VERSION 5.7 ;
BUSBITCHARS "[]" ;
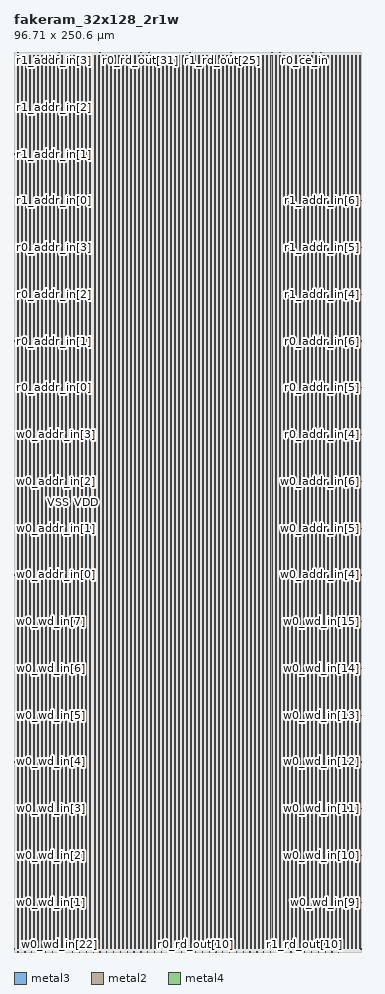
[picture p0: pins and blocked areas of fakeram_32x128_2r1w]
MACRO fakeram_32x128_2r1w
  FOREIGN fakeram_32x128_2r1w 0 0 ;
  SYMMETRY X Y R90 ;
  SIZE 96.710 BY 250.600 ;
  CLASS BLOCK ;
  PIN w0_wd_in[0]
    DIRECTION INPUT ;
    USE SIGNAL ;
    SHAPE ABUTMENT ;
    PORT
      LAYER metal3 ;
      RECT 0.000 0.805 0.210 0.875 ;
    END
  END w0_wd_in[0]
  PIN w0_wd_in[1]
    DIRECTION INPUT ;
    USE SIGNAL ;
    SHAPE ABUTMENT ;
    PORT
      LAYER metal3 ;
      RECT 0.000 13.825 0.210 13.895 ;
    END
  END w0_wd_in[1]
  PIN w0_wd_in[2]
    DIRECTION INPUT ;
    USE SIGNAL ;
    SHAPE ABUTMENT ;
    PORT
      LAYER metal3 ;
      RECT 0.000 26.845 0.210 26.915 ;
    END
  END w0_wd_in[2]
  PIN w0_wd_in[3]
    DIRECTION INPUT ;
    USE SIGNAL ;
    SHAPE ABUTMENT ;
    PORT
      LAYER metal3 ;
      RECT 0.000 39.865 0.210 39.935 ;
    END
  END w0_wd_in[3]
  PIN w0_wd_in[4]
    DIRECTION INPUT ;
    USE SIGNAL ;
    SHAPE ABUTMENT ;
    PORT
      LAYER metal3 ;
      RECT 0.000 52.885 0.210 52.955 ;
    END
  END w0_wd_in[4]
  PIN w0_wd_in[5]
    DIRECTION INPUT ;
    USE SIGNAL ;
    SHAPE ABUTMENT ;
    PORT
      LAYER metal3 ;
      RECT 0.000 65.905 0.210 65.975 ;
    END
  END w0_wd_in[5]
  PIN w0_wd_in[6]
    DIRECTION INPUT ;
    USE SIGNAL ;
    SHAPE ABUTMENT ;
    PORT
      LAYER metal3 ;
      RECT 0.000 78.925 0.210 78.995 ;
    END
  END w0_wd_in[6]
  PIN w0_wd_in[7]
    DIRECTION INPUT ;
    USE SIGNAL ;
    SHAPE ABUTMENT ;
    PORT
      LAYER metal3 ;
      RECT 0.000 91.945 0.210 92.015 ;
    END
  END w0_wd_in[7]
  PIN w0_wd_in[8]
    DIRECTION INPUT ;
    USE SIGNAL ;
    SHAPE ABUTMENT ;
    PORT
      LAYER metal3 ;
      RECT 96.500 0.805 96.710 0.875 ;
    END
  END w0_wd_in[8]
  PIN w0_wd_in[9]
    DIRECTION INPUT ;
    USE SIGNAL ;
    SHAPE ABUTMENT ;
    PORT
      LAYER metal3 ;
      RECT 96.500 13.825 96.710 13.895 ;
    END
  END w0_wd_in[9]
  PIN w0_wd_in[10]
    DIRECTION INPUT ;
    USE SIGNAL ;
    SHAPE ABUTMENT ;
    PORT
      LAYER metal3 ;
      RECT 96.500 26.845 96.710 26.915 ;
    END
  END w0_wd_in[10]
  PIN w0_wd_in[11]
    DIRECTION INPUT ;
    USE SIGNAL ;
    SHAPE ABUTMENT ;
    PORT
      LAYER metal3 ;
      RECT 96.500 39.865 96.710 39.935 ;
    END
  END w0_wd_in[11]
  PIN w0_wd_in[12]
    DIRECTION INPUT ;
    USE SIGNAL ;
    SHAPE ABUTMENT ;
    PORT
      LAYER metal3 ;
      RECT 96.500 52.885 96.710 52.955 ;
    END
  END w0_wd_in[12]
  PIN w0_wd_in[13]
    DIRECTION INPUT ;
    USE SIGNAL ;
    SHAPE ABUTMENT ;
    PORT
      LAYER metal3 ;
      RECT 96.500 65.905 96.710 65.975 ;
    END
  END w0_wd_in[13]
  PIN w0_wd_in[14]
    DIRECTION INPUT ;
    USE SIGNAL ;
    SHAPE ABUTMENT ;
    PORT
      LAYER metal3 ;
      RECT 96.500 78.925 96.710 78.995 ;
    END
  END w0_wd_in[14]
  PIN w0_wd_in[15]
    DIRECTION INPUT ;
    USE SIGNAL ;
    SHAPE ABUTMENT ;
    PORT
      LAYER metal3 ;
      RECT 96.500 91.945 96.710 92.015 ;
    END
  END w0_wd_in[15]
  PIN w0_wd_in[16]
    DIRECTION INPUT ;
    USE SIGNAL ;
    SHAPE ABUTMENT ;
    PORT
      LAYER metal2 ;
      RECT 1.105 0.000 1.175 0.210 ;
    END
  END w0_wd_in[16]
  PIN w0_wd_in[17]
    DIRECTION INPUT ;
    USE SIGNAL ;
    SHAPE ABUTMENT ;
    PORT
      LAYER metal2 ;
      RECT 3.005 0.000 3.075 0.210 ;
    END
  END w0_wd_in[17]
  PIN w0_wd_in[18]
    DIRECTION INPUT ;
    USE SIGNAL ;
    SHAPE ABUTMENT ;
    PORT
      LAYER metal2 ;
      RECT 4.905 0.000 4.975 0.210 ;
    END
  END w0_wd_in[18]
  PIN w0_wd_in[19]
    DIRECTION INPUT ;
    USE SIGNAL ;
    SHAPE ABUTMENT ;
    PORT
      LAYER metal2 ;
      RECT 6.805 0.000 6.875 0.210 ;
    END
  END w0_wd_in[19]
  PIN w0_wd_in[20]
    DIRECTION INPUT ;
    USE SIGNAL ;
    SHAPE ABUTMENT ;
    PORT
      LAYER metal2 ;
      RECT 8.705 0.000 8.775 0.210 ;
    END
  END w0_wd_in[20]
  PIN w0_wd_in[21]
    DIRECTION INPUT ;
    USE SIGNAL ;
    SHAPE ABUTMENT ;
    PORT
      LAYER metal2 ;
      RECT 10.605 0.000 10.675 0.210 ;
    END
  END w0_wd_in[21]
  PIN w0_wd_in[22]
    DIRECTION INPUT ;
    USE SIGNAL ;
    SHAPE ABUTMENT ;
    PORT
      LAYER metal2 ;
      RECT 12.505 0.000 12.575 0.210 ;
    END
  END w0_wd_in[22]
  PIN w0_wd_in[23]
    DIRECTION INPUT ;
    USE SIGNAL ;
    SHAPE ABUTMENT ;
    PORT
      LAYER metal2 ;
      RECT 14.405 0.000 14.475 0.210 ;
    END
  END w0_wd_in[23]
  PIN w0_wd_in[24]
    DIRECTION INPUT ;
    USE SIGNAL ;
    SHAPE ABUTMENT ;
    PORT
      LAYER metal2 ;
      RECT 16.305 0.000 16.375 0.210 ;
    END
  END w0_wd_in[24]
  PIN w0_wd_in[25]
    DIRECTION INPUT ;
    USE SIGNAL ;
    SHAPE ABUTMENT ;
    PORT
      LAYER metal2 ;
      RECT 18.205 0.000 18.275 0.210 ;
    END
  END w0_wd_in[25]
  PIN w0_wd_in[26]
    DIRECTION INPUT ;
    USE SIGNAL ;
    SHAPE ABUTMENT ;
    PORT
      LAYER metal2 ;
      RECT 20.105 0.000 20.175 0.210 ;
    END
  END w0_wd_in[26]
  PIN w0_wd_in[27]
    DIRECTION INPUT ;
    USE SIGNAL ;
    SHAPE ABUTMENT ;
    PORT
      LAYER metal2 ;
      RECT 22.005 0.000 22.075 0.210 ;
    END
  END w0_wd_in[27]
  PIN w0_wd_in[28]
    DIRECTION INPUT ;
    USE SIGNAL ;
    SHAPE ABUTMENT ;
    PORT
      LAYER metal2 ;
      RECT 23.905 0.000 23.975 0.210 ;
    END
  END w0_wd_in[28]
  PIN w0_wd_in[29]
    DIRECTION INPUT ;
    USE SIGNAL ;
    SHAPE ABUTMENT ;
    PORT
      LAYER metal2 ;
      RECT 25.805 0.000 25.875 0.210 ;
    END
  END w0_wd_in[29]
  PIN w0_wd_in[30]
    DIRECTION INPUT ;
    USE SIGNAL ;
    SHAPE ABUTMENT ;
    PORT
      LAYER metal2 ;
      RECT 27.705 0.000 27.775 0.210 ;
    END
  END w0_wd_in[30]
  PIN w0_wd_in[31]
    DIRECTION INPUT ;
    USE SIGNAL ;
    SHAPE ABUTMENT ;
    PORT
      LAYER metal2 ;
      RECT 29.605 0.000 29.675 0.210 ;
    END
  END w0_wd_in[31]
  PIN r0_rd_out[0]
    DIRECTION OUTPUT ;
    USE SIGNAL ;
    SHAPE ABUTMENT ;
    PORT
      LAYER metal2 ;
      RECT 31.505 0.000 31.575 0.210 ;
    END
  END r0_rd_out[0]
  PIN r0_rd_out[1]
    DIRECTION OUTPUT ;
    USE SIGNAL ;
    SHAPE ABUTMENT ;
    PORT
      LAYER metal2 ;
      RECT 33.405 0.000 33.475 0.210 ;
    END
  END r0_rd_out[1]
  PIN r0_rd_out[2]
    DIRECTION OUTPUT ;
    USE SIGNAL ;
    SHAPE ABUTMENT ;
    PORT
      LAYER metal2 ;
      RECT 35.305 0.000 35.375 0.210 ;
    END
  END r0_rd_out[2]
  PIN r0_rd_out[3]
    DIRECTION OUTPUT ;
    USE SIGNAL ;
    SHAPE ABUTMENT ;
    PORT
      LAYER metal2 ;
      RECT 37.205 0.000 37.275 0.210 ;
    END
  END r0_rd_out[3]
  PIN r0_rd_out[4]
    DIRECTION OUTPUT ;
    USE SIGNAL ;
    SHAPE ABUTMENT ;
    PORT
      LAYER metal2 ;
      RECT 39.105 0.000 39.175 0.210 ;
    END
  END r0_rd_out[4]
  PIN r0_rd_out[5]
    DIRECTION OUTPUT ;
    USE SIGNAL ;
    SHAPE ABUTMENT ;
    PORT
      LAYER metal2 ;
      RECT 41.005 0.000 41.075 0.210 ;
    END
  END r0_rd_out[5]
  PIN r0_rd_out[6]
    DIRECTION OUTPUT ;
    USE SIGNAL ;
    SHAPE ABUTMENT ;
    PORT
      LAYER metal2 ;
      RECT 42.905 0.000 42.975 0.210 ;
    END
  END r0_rd_out[6]
  PIN r0_rd_out[7]
    DIRECTION OUTPUT ;
    USE SIGNAL ;
    SHAPE ABUTMENT ;
    PORT
      LAYER metal2 ;
      RECT 44.805 0.000 44.875 0.210 ;
    END
  END r0_rd_out[7]
  PIN r0_rd_out[8]
    DIRECTION OUTPUT ;
    USE SIGNAL ;
    SHAPE ABUTMENT ;
    PORT
      LAYER metal2 ;
      RECT 46.705 0.000 46.775 0.210 ;
    END
  END r0_rd_out[8]
  PIN r0_rd_out[9]
    DIRECTION OUTPUT ;
    USE SIGNAL ;
    SHAPE ABUTMENT ;
    PORT
      LAYER metal2 ;
      RECT 48.605 0.000 48.675 0.210 ;
    END
  END r0_rd_out[9]
  PIN r0_rd_out[10]
    DIRECTION OUTPUT ;
    USE SIGNAL ;
    SHAPE ABUTMENT ;
    PORT
      LAYER metal2 ;
      RECT 50.505 0.000 50.575 0.210 ;
    END
  END r0_rd_out[10]
  PIN r0_rd_out[11]
    DIRECTION OUTPUT ;
    USE SIGNAL ;
    SHAPE ABUTMENT ;
    PORT
      LAYER metal2 ;
      RECT 52.405 0.000 52.475 0.210 ;
    END
  END r0_rd_out[11]
  PIN r0_rd_out[12]
    DIRECTION OUTPUT ;
    USE SIGNAL ;
    SHAPE ABUTMENT ;
    PORT
      LAYER metal2 ;
      RECT 54.305 0.000 54.375 0.210 ;
    END
  END r0_rd_out[12]
  PIN r0_rd_out[13]
    DIRECTION OUTPUT ;
    USE SIGNAL ;
    SHAPE ABUTMENT ;
    PORT
      LAYER metal2 ;
      RECT 56.205 0.000 56.275 0.210 ;
    END
  END r0_rd_out[13]
  PIN r0_rd_out[14]
    DIRECTION OUTPUT ;
    USE SIGNAL ;
    SHAPE ABUTMENT ;
    PORT
      LAYER metal2 ;
      RECT 58.105 0.000 58.175 0.210 ;
    END
  END r0_rd_out[14]
  PIN r0_rd_out[15]
    DIRECTION OUTPUT ;
    USE SIGNAL ;
    SHAPE ABUTMENT ;
    PORT
      LAYER metal2 ;
      RECT 60.005 0.000 60.075 0.210 ;
    END
  END r0_rd_out[15]
  PIN r0_rd_out[16]
    DIRECTION OUTPUT ;
    USE SIGNAL ;
    SHAPE ABUTMENT ;
    PORT
      LAYER metal2 ;
      RECT 1.105 250.390 1.175 250.600 ;
    END
  END r0_rd_out[16]
  PIN r0_rd_out[17]
    DIRECTION OUTPUT ;
    USE SIGNAL ;
    SHAPE ABUTMENT ;
    PORT
      LAYER metal2 ;
      RECT 3.385 250.390 3.455 250.600 ;
    END
  END r0_rd_out[17]
  PIN r0_rd_out[18]
    DIRECTION OUTPUT ;
    USE SIGNAL ;
    SHAPE ABUTMENT ;
    PORT
      LAYER metal2 ;
      RECT 5.665 250.390 5.735 250.600 ;
    END
  END r0_rd_out[18]
  PIN r0_rd_out[19]
    DIRECTION OUTPUT ;
    USE SIGNAL ;
    SHAPE ABUTMENT ;
    PORT
      LAYER metal2 ;
      RECT 7.945 250.390 8.015 250.600 ;
    END
  END r0_rd_out[19]
  PIN r0_rd_out[20]
    DIRECTION OUTPUT ;
    USE SIGNAL ;
    SHAPE ABUTMENT ;
    PORT
      LAYER metal2 ;
      RECT 10.225 250.390 10.295 250.600 ;
    END
  END r0_rd_out[20]
  PIN r0_rd_out[21]
    DIRECTION OUTPUT ;
    USE SIGNAL ;
    SHAPE ABUTMENT ;
    PORT
      LAYER metal2 ;
      RECT 12.505 250.390 12.575 250.600 ;
    END
  END r0_rd_out[21]
  PIN r0_rd_out[22]
    DIRECTION OUTPUT ;
    USE SIGNAL ;
    SHAPE ABUTMENT ;
    PORT
      LAYER metal2 ;
      RECT 14.785 250.390 14.855 250.600 ;
    END
  END r0_rd_out[22]
  PIN r0_rd_out[23]
    DIRECTION OUTPUT ;
    USE SIGNAL ;
    SHAPE ABUTMENT ;
    PORT
      LAYER metal2 ;
      RECT 17.065 250.390 17.135 250.600 ;
    END
  END r0_rd_out[23]
  PIN r0_rd_out[24]
    DIRECTION OUTPUT ;
    USE SIGNAL ;
    SHAPE ABUTMENT ;
    PORT
      LAYER metal2 ;
      RECT 19.345 250.390 19.415 250.600 ;
    END
  END r0_rd_out[24]
  PIN r0_rd_out[25]
    DIRECTION OUTPUT ;
    USE SIGNAL ;
    SHAPE ABUTMENT ;
    PORT
      LAYER metal2 ;
      RECT 21.625 250.390 21.695 250.600 ;
    END
  END r0_rd_out[25]
  PIN r0_rd_out[26]
    DIRECTION OUTPUT ;
    USE SIGNAL ;
    SHAPE ABUTMENT ;
    PORT
      LAYER metal2 ;
      RECT 23.905 250.390 23.975 250.600 ;
    END
  END r0_rd_out[26]
  PIN r0_rd_out[27]
    DIRECTION OUTPUT ;
    USE SIGNAL ;
    SHAPE ABUTMENT ;
    PORT
      LAYER metal2 ;
      RECT 26.185 250.390 26.255 250.600 ;
    END
  END r0_rd_out[27]
  PIN r0_rd_out[28]
    DIRECTION OUTPUT ;
    USE SIGNAL ;
    SHAPE ABUTMENT ;
    PORT
      LAYER metal2 ;
      RECT 28.465 250.390 28.535 250.600 ;
    END
  END r0_rd_out[28]
  PIN r0_rd_out[29]
    DIRECTION OUTPUT ;
    USE SIGNAL ;
    SHAPE ABUTMENT ;
    PORT
      LAYER metal2 ;
      RECT 30.745 250.390 30.815 250.600 ;
    END
  END r0_rd_out[29]
  PIN r0_rd_out[30]
    DIRECTION OUTPUT ;
    USE SIGNAL ;
    SHAPE ABUTMENT ;
    PORT
      LAYER metal2 ;
      RECT 33.025 250.390 33.095 250.600 ;
    END
  END r0_rd_out[30]
  PIN r0_rd_out[31]
    DIRECTION OUTPUT ;
    USE SIGNAL ;
    SHAPE ABUTMENT ;
    PORT
      LAYER metal2 ;
      RECT 35.305 250.390 35.375 250.600 ;
    END
  END r0_rd_out[31]
  PIN r1_rd_out[0]
    DIRECTION OUTPUT ;
    USE SIGNAL ;
    SHAPE ABUTMENT ;
    PORT
      LAYER metal2 ;
      RECT 61.905 0.000 61.975 0.210 ;
    END
  END r1_rd_out[0]
  PIN r1_rd_out[1]
    DIRECTION OUTPUT ;
    USE SIGNAL ;
    SHAPE ABUTMENT ;
    PORT
      LAYER metal2 ;
      RECT 63.805 0.000 63.875 0.210 ;
    END
  END r1_rd_out[1]
  PIN r1_rd_out[2]
    DIRECTION OUTPUT ;
    USE SIGNAL ;
    SHAPE ABUTMENT ;
    PORT
      LAYER metal2 ;
      RECT 65.705 0.000 65.775 0.210 ;
    END
  END r1_rd_out[2]
  PIN r1_rd_out[3]
    DIRECTION OUTPUT ;
    USE SIGNAL ;
    SHAPE ABUTMENT ;
    PORT
      LAYER metal2 ;
      RECT 67.605 0.000 67.675 0.210 ;
    END
  END r1_rd_out[3]
  PIN r1_rd_out[4]
    DIRECTION OUTPUT ;
    USE SIGNAL ;
    SHAPE ABUTMENT ;
    PORT
      LAYER metal2 ;
      RECT 69.505 0.000 69.575 0.210 ;
    END
  END r1_rd_out[4]
  PIN r1_rd_out[5]
    DIRECTION OUTPUT ;
    USE SIGNAL ;
    SHAPE ABUTMENT ;
    PORT
      LAYER metal2 ;
      RECT 71.405 0.000 71.475 0.210 ;
    END
  END r1_rd_out[5]
  PIN r1_rd_out[6]
    DIRECTION OUTPUT ;
    USE SIGNAL ;
    SHAPE ABUTMENT ;
    PORT
      LAYER metal2 ;
      RECT 73.305 0.000 73.375 0.210 ;
    END
  END r1_rd_out[6]
  PIN r1_rd_out[7]
    DIRECTION OUTPUT ;
    USE SIGNAL ;
    SHAPE ABUTMENT ;
    PORT
      LAYER metal2 ;
      RECT 75.205 0.000 75.275 0.210 ;
    END
  END r1_rd_out[7]
  PIN r1_rd_out[8]
    DIRECTION OUTPUT ;
    USE SIGNAL ;
    SHAPE ABUTMENT ;
    PORT
      LAYER metal2 ;
      RECT 77.105 0.000 77.175 0.210 ;
    END
  END r1_rd_out[8]
  PIN r1_rd_out[9]
    DIRECTION OUTPUT ;
    USE SIGNAL ;
    SHAPE ABUTMENT ;
    PORT
      LAYER metal2 ;
      RECT 79.005 0.000 79.075 0.210 ;
    END
  END r1_rd_out[9]
  PIN r1_rd_out[10]
    DIRECTION OUTPUT ;
    USE SIGNAL ;
    SHAPE ABUTMENT ;
    PORT
      LAYER metal2 ;
      RECT 80.905 0.000 80.975 0.210 ;
    END
  END r1_rd_out[10]
  PIN r1_rd_out[11]
    DIRECTION OUTPUT ;
    USE SIGNAL ;
    SHAPE ABUTMENT ;
    PORT
      LAYER metal2 ;
      RECT 82.805 0.000 82.875 0.210 ;
    END
  END r1_rd_out[11]
  PIN r1_rd_out[12]
    DIRECTION OUTPUT ;
    USE SIGNAL ;
    SHAPE ABUTMENT ;
    PORT
      LAYER metal2 ;
      RECT 84.705 0.000 84.775 0.210 ;
    END
  END r1_rd_out[12]
  PIN r1_rd_out[13]
    DIRECTION OUTPUT ;
    USE SIGNAL ;
    SHAPE ABUTMENT ;
    PORT
      LAYER metal2 ;
      RECT 86.605 0.000 86.675 0.210 ;
    END
  END r1_rd_out[13]
  PIN r1_rd_out[14]
    DIRECTION OUTPUT ;
    USE SIGNAL ;
    SHAPE ABUTMENT ;
    PORT
      LAYER metal2 ;
      RECT 88.505 0.000 88.575 0.210 ;
    END
  END r1_rd_out[14]
  PIN r1_rd_out[15]
    DIRECTION OUTPUT ;
    USE SIGNAL ;
    SHAPE ABUTMENT ;
    PORT
      LAYER metal2 ;
      RECT 90.405 0.000 90.475 0.210 ;
    END
  END r1_rd_out[15]
  PIN r1_rd_out[16]
    DIRECTION OUTPUT ;
    USE SIGNAL ;
    SHAPE ABUTMENT ;
    PORT
      LAYER metal2 ;
      RECT 37.585 250.390 37.655 250.600 ;
    END
  END r1_rd_out[16]
  PIN r1_rd_out[17]
    DIRECTION OUTPUT ;
    USE SIGNAL ;
    SHAPE ABUTMENT ;
    PORT
      LAYER metal2 ;
      RECT 39.865 250.390 39.935 250.600 ;
    END
  END r1_rd_out[17]
  PIN r1_rd_out[18]
    DIRECTION OUTPUT ;
    USE SIGNAL ;
    SHAPE ABUTMENT ;
    PORT
      LAYER metal2 ;
      RECT 42.145 250.390 42.215 250.600 ;
    END
  END r1_rd_out[18]
  PIN r1_rd_out[19]
    DIRECTION OUTPUT ;
    USE SIGNAL ;
    SHAPE ABUTMENT ;
    PORT
      LAYER metal2 ;
      RECT 44.425 250.390 44.495 250.600 ;
    END
  END r1_rd_out[19]
  PIN r1_rd_out[20]
    DIRECTION OUTPUT ;
    USE SIGNAL ;
    SHAPE ABUTMENT ;
    PORT
      LAYER metal2 ;
      RECT 46.705 250.390 46.775 250.600 ;
    END
  END r1_rd_out[20]
  PIN r1_rd_out[21]
    DIRECTION OUTPUT ;
    USE SIGNAL ;
    SHAPE ABUTMENT ;
    PORT
      LAYER metal2 ;
      RECT 48.985 250.390 49.055 250.600 ;
    END
  END r1_rd_out[21]
  PIN r1_rd_out[22]
    DIRECTION OUTPUT ;
    USE SIGNAL ;
    SHAPE ABUTMENT ;
    PORT
      LAYER metal2 ;
      RECT 51.265 250.390 51.335 250.600 ;
    END
  END r1_rd_out[22]
  PIN r1_rd_out[23]
    DIRECTION OUTPUT ;
    USE SIGNAL ;
    SHAPE ABUTMENT ;
    PORT
      LAYER metal2 ;
      RECT 53.545 250.390 53.615 250.600 ;
    END
  END r1_rd_out[23]
  PIN r1_rd_out[24]
    DIRECTION OUTPUT ;
    USE SIGNAL ;
    SHAPE ABUTMENT ;
    PORT
      LAYER metal2 ;
      RECT 55.825 250.390 55.895 250.600 ;
    END
  END r1_rd_out[24]
  PIN r1_rd_out[25]
    DIRECTION OUTPUT ;
    USE SIGNAL ;
    SHAPE ABUTMENT ;
    PORT
      LAYER metal2 ;
      RECT 58.105 250.390 58.175 250.600 ;
    END
  END r1_rd_out[25]
  PIN r1_rd_out[26]
    DIRECTION OUTPUT ;
    USE SIGNAL ;
    SHAPE ABUTMENT ;
    PORT
      LAYER metal2 ;
      RECT 60.385 250.390 60.455 250.600 ;
    END
  END r1_rd_out[26]
  PIN r1_rd_out[27]
    DIRECTION OUTPUT ;
    USE SIGNAL ;
    SHAPE ABUTMENT ;
    PORT
      LAYER metal2 ;
      RECT 62.665 250.390 62.735 250.600 ;
    END
  END r1_rd_out[27]
  PIN r1_rd_out[28]
    DIRECTION OUTPUT ;
    USE SIGNAL ;
    SHAPE ABUTMENT ;
    PORT
      LAYER metal2 ;
      RECT 64.945 250.390 65.015 250.600 ;
    END
  END r1_rd_out[28]
  PIN r1_rd_out[29]
    DIRECTION OUTPUT ;
    USE SIGNAL ;
    SHAPE ABUTMENT ;
    PORT
      LAYER metal2 ;
      RECT 67.225 250.390 67.295 250.600 ;
    END
  END r1_rd_out[29]
  PIN r1_rd_out[30]
    DIRECTION OUTPUT ;
    USE SIGNAL ;
    SHAPE ABUTMENT ;
    PORT
      LAYER metal2 ;
      RECT 69.505 250.390 69.575 250.600 ;
    END
  END r1_rd_out[30]
  PIN r1_rd_out[31]
    DIRECTION OUTPUT ;
    USE SIGNAL ;
    SHAPE ABUTMENT ;
    PORT
      LAYER metal2 ;
      RECT 71.785 250.390 71.855 250.600 ;
    END
  END r1_rd_out[31]
  PIN w0_addr_in[0]
    DIRECTION INPUT ;
    USE SIGNAL ;
    SHAPE ABUTMENT ;
    PORT
      LAYER metal3 ;
      RECT 0.000 104.965 0.210 105.035 ;
    END
  END w0_addr_in[0]
  PIN w0_addr_in[1]
    DIRECTION INPUT ;
    USE SIGNAL ;
    SHAPE ABUTMENT ;
    PORT
      LAYER metal3 ;
      RECT 0.000 117.985 0.210 118.055 ;
    END
  END w0_addr_in[1]
  PIN w0_addr_in[2]
    DIRECTION INPUT ;
    USE SIGNAL ;
    SHAPE ABUTMENT ;
    PORT
      LAYER metal3 ;
      RECT 0.000 131.005 0.210 131.075 ;
    END
  END w0_addr_in[2]
  PIN w0_addr_in[3]
    DIRECTION INPUT ;
    USE SIGNAL ;
    SHAPE ABUTMENT ;
    PORT
      LAYER metal3 ;
      RECT 0.000 144.025 0.210 144.095 ;
    END
  END w0_addr_in[3]
  PIN w0_addr_in[4]
    DIRECTION INPUT ;
    USE SIGNAL ;
    SHAPE ABUTMENT ;
    PORT
      LAYER metal3 ;
      RECT 96.500 104.965 96.710 105.035 ;
    END
  END w0_addr_in[4]
  PIN w0_addr_in[5]
    DIRECTION INPUT ;
    USE SIGNAL ;
    SHAPE ABUTMENT ;
    PORT
      LAYER metal3 ;
      RECT 96.500 117.985 96.710 118.055 ;
    END
  END w0_addr_in[5]
  PIN w0_addr_in[6]
    DIRECTION INPUT ;
    USE SIGNAL ;
    SHAPE ABUTMENT ;
    PORT
      LAYER metal3 ;
      RECT 96.500 131.005 96.710 131.075 ;
    END
  END w0_addr_in[6]
  PIN r0_addr_in[0]
    DIRECTION INPUT ;
    USE SIGNAL ;
    SHAPE ABUTMENT ;
    PORT
      LAYER metal3 ;
      RECT 0.000 157.045 0.210 157.115 ;
    END
  END r0_addr_in[0]
  PIN r0_addr_in[1]
    DIRECTION INPUT ;
    USE SIGNAL ;
    SHAPE ABUTMENT ;
    PORT
      LAYER metal3 ;
      RECT 0.000 170.065 0.210 170.135 ;
    END
  END r0_addr_in[1]
  PIN r0_addr_in[2]
    DIRECTION INPUT ;
    USE SIGNAL ;
    SHAPE ABUTMENT ;
    PORT
      LAYER metal3 ;
      RECT 0.000 183.085 0.210 183.155 ;
    END
  END r0_addr_in[2]
  PIN r0_addr_in[3]
    DIRECTION INPUT ;
    USE SIGNAL ;
    SHAPE ABUTMENT ;
    PORT
      LAYER metal3 ;
      RECT 0.000 196.105 0.210 196.175 ;
    END
  END r0_addr_in[3]
  PIN r0_addr_in[4]
    DIRECTION INPUT ;
    USE SIGNAL ;
    SHAPE ABUTMENT ;
    PORT
      LAYER metal3 ;
      RECT 96.500 144.025 96.710 144.095 ;
    END
  END r0_addr_in[4]
  PIN r0_addr_in[5]
    DIRECTION INPUT ;
    USE SIGNAL ;
    SHAPE ABUTMENT ;
    PORT
      LAYER metal3 ;
      RECT 96.500 157.045 96.710 157.115 ;
    END
  END r0_addr_in[5]
  PIN r0_addr_in[6]
    DIRECTION INPUT ;
    USE SIGNAL ;
    SHAPE ABUTMENT ;
    PORT
      LAYER metal3 ;
      RECT 96.500 170.065 96.710 170.135 ;
    END
  END r0_addr_in[6]
  PIN r1_addr_in[0]
    DIRECTION INPUT ;
    USE SIGNAL ;
    SHAPE ABUTMENT ;
    PORT
      LAYER metal3 ;
      RECT 0.000 209.125 0.210 209.195 ;
    END
  END r1_addr_in[0]
  PIN r1_addr_in[1]
    DIRECTION INPUT ;
    USE SIGNAL ;
    SHAPE ABUTMENT ;
    PORT
      LAYER metal3 ;
      RECT 0.000 222.145 0.210 222.215 ;
    END
  END r1_addr_in[1]
  PIN r1_addr_in[2]
    DIRECTION INPUT ;
    USE SIGNAL ;
    SHAPE ABUTMENT ;
    PORT
      LAYER metal3 ;
      RECT 0.000 235.165 0.210 235.235 ;
    END
  END r1_addr_in[2]
  PIN r1_addr_in[3]
    DIRECTION INPUT ;
    USE SIGNAL ;
    SHAPE ABUTMENT ;
    PORT
      LAYER metal3 ;
      RECT 0.000 248.185 0.210 248.255 ;
    END
  END r1_addr_in[3]
  PIN r1_addr_in[4]
    DIRECTION INPUT ;
    USE SIGNAL ;
    SHAPE ABUTMENT ;
    PORT
      LAYER metal3 ;
      RECT 96.500 183.085 96.710 183.155 ;
    END
  END r1_addr_in[4]
  PIN r1_addr_in[5]
    DIRECTION INPUT ;
    USE SIGNAL ;
    SHAPE ABUTMENT ;
    PORT
      LAYER metal3 ;
      RECT 96.500 196.105 96.710 196.175 ;
    END
  END r1_addr_in[5]
  PIN r1_addr_in[6]
    DIRECTION INPUT ;
    USE SIGNAL ;
    SHAPE ABUTMENT ;
    PORT
      LAYER metal3 ;
      RECT 96.500 209.125 96.710 209.195 ;
    END
  END r1_addr_in[6]
  PIN w0_we_in
    DIRECTION INPUT ;
    USE SIGNAL ;
    SHAPE ABUTMENT ;
    PORT
      LAYER metal2 ;
      RECT 74.065 250.390 74.135 250.600 ;
    END
  END w0_we_in
  PIN w0_ce_in
    DIRECTION INPUT ;
    USE SIGNAL ;
    SHAPE ABUTMENT ;
    PORT
      LAYER metal2 ;
      RECT 76.345 250.390 76.415 250.600 ;
    END
  END w0_ce_in
  PIN w0_clk
    DIRECTION INPUT ;
    USE SIGNAL ;
    SHAPE ABUTMENT ;
    PORT
      LAYER metal2 ;
      RECT 78.625 250.390 78.695 250.600 ;
    END
  END w0_clk
  PIN r0_ce_in
    DIRECTION INPUT ;
    USE SIGNAL ;
    SHAPE ABUTMENT ;
    PORT
      LAYER metal2 ;
      RECT 80.905 250.390 80.975 250.600 ;
    END
  END r0_ce_in
  PIN r0_clk
    DIRECTION INPUT ;
    USE SIGNAL ;
    SHAPE ABUTMENT ;
    PORT
      LAYER metal2 ;
      RECT 83.185 250.390 83.255 250.600 ;
    END
  END r0_clk
  PIN r1_ce_in
    DIRECTION INPUT ;
    USE SIGNAL ;
    SHAPE ABUTMENT ;
    PORT
      LAYER metal2 ;
      RECT 85.465 250.390 85.535 250.600 ;
    END
  END r1_ce_in
  PIN r1_clk
    DIRECTION INPUT ;
    USE SIGNAL ;
    SHAPE ABUTMENT ;
    PORT
      LAYER metal2 ;
      RECT 87.745 250.390 87.815 250.600 ;
    END
  END r1_clk
  PIN VSS
    DIRECTION INOUT ;
    USE GROUND ;
    PORT
      LAYER metal4 ;
      RECT 1.000 0.840 1.280 249.760 ;
      RECT 3.240 0.840 3.520 249.760 ;
      RECT 5.480 0.840 5.760 249.760 ;
      RECT 7.720 0.840 8.000 249.760 ;
      RECT 9.960 0.840 10.240 249.760 ;
      RECT 12.200 0.840 12.480 249.760 ;
      RECT 14.440 0.840 14.720 249.760 ;
      RECT 16.680 0.840 16.960 249.760 ;
      RECT 18.920 0.840 19.200 249.760 ;
      RECT 21.160 0.840 21.440 249.760 ;
      RECT 23.400 0.840 23.680 249.760 ;
      RECT 25.640 0.840 25.920 249.760 ;
      RECT 27.880 0.840 28.160 249.760 ;
      RECT 30.120 0.840 30.400 249.760 ;
      RECT 32.360 0.840 32.640 249.760 ;
      RECT 34.600 0.840 34.880 249.760 ;
      RECT 36.840 0.840 37.120 249.760 ;
      RECT 39.080 0.840 39.360 249.760 ;
      RECT 41.320 0.840 41.600 249.760 ;
      RECT 43.560 0.840 43.840 249.760 ;
      RECT 45.800 0.840 46.080 249.760 ;
      RECT 48.040 0.840 48.320 249.760 ;
      RECT 50.280 0.840 50.560 249.760 ;
      RECT 52.520 0.840 52.800 249.760 ;
      RECT 54.760 0.840 55.040 249.760 ;
      RECT 57.000 0.840 57.280 249.760 ;
      RECT 59.240 0.840 59.520 249.760 ;
      RECT 61.480 0.840 61.760 249.760 ;
      RECT 63.720 0.840 64.000 249.760 ;
      RECT 65.960 0.840 66.240 249.760 ;
      RECT 68.200 0.840 68.480 249.760 ;
      RECT 70.440 0.840 70.720 249.760 ;
      RECT 72.680 0.840 72.960 249.760 ;
      RECT 74.920 0.840 75.200 249.760 ;
      RECT 77.160 0.840 77.440 249.760 ;
      RECT 79.400 0.840 79.680 249.760 ;
      RECT 81.640 0.840 81.920 249.760 ;
      RECT 83.880 0.840 84.160 249.760 ;
      RECT 86.120 0.840 86.400 249.760 ;
      RECT 88.360 0.840 88.640 249.760 ;
      RECT 90.600 0.840 90.880 249.760 ;
      RECT 92.840 0.840 93.120 249.760 ;
      RECT 95.080 0.840 95.360 249.760 ;
    END
  END VSS
  PIN VDD
    DIRECTION INOUT ;
    USE POWER ;
    PORT
      LAYER metal4 ;
      RECT 2.120 0.840 2.400 249.760 ;
      RECT 4.360 0.840 4.640 249.760 ;
      RECT 6.600 0.840 6.880 249.760 ;
      RECT 8.840 0.840 9.120 249.760 ;
      RECT 11.080 0.840 11.360 249.760 ;
      RECT 13.320 0.840 13.600 249.760 ;
      RECT 15.560 0.840 15.840 249.760 ;
      RECT 17.800 0.840 18.080 249.760 ;
      RECT 20.040 0.840 20.320 249.760 ;
      RECT 22.280 0.840 22.560 249.760 ;
      RECT 24.520 0.840 24.800 249.760 ;
      RECT 26.760 0.840 27.040 249.760 ;
      RECT 29.000 0.840 29.280 249.760 ;
      RECT 31.240 0.840 31.520 249.760 ;
      RECT 33.480 0.840 33.760 249.760 ;
      RECT 35.720 0.840 36.000 249.760 ;
      RECT 37.960 0.840 38.240 249.760 ;
      RECT 40.200 0.840 40.480 249.760 ;
      RECT 42.440 0.840 42.720 249.760 ;
      RECT 44.680 0.840 44.960 249.760 ;
      RECT 46.920 0.840 47.200 249.760 ;
      RECT 49.160 0.840 49.440 249.760 ;
      RECT 51.400 0.840 51.680 249.760 ;
      RECT 53.640 0.840 53.920 249.760 ;
      RECT 55.880 0.840 56.160 249.760 ;
      RECT 58.120 0.840 58.400 249.760 ;
      RECT 60.360 0.840 60.640 249.760 ;
      RECT 62.600 0.840 62.880 249.760 ;
      RECT 64.840 0.840 65.120 249.760 ;
      RECT 67.080 0.840 67.360 249.760 ;
      RECT 69.320 0.840 69.600 249.760 ;
      RECT 71.560 0.840 71.840 249.760 ;
      RECT 73.800 0.840 74.080 249.760 ;
      RECT 76.040 0.840 76.320 249.760 ;
      RECT 78.280 0.840 78.560 249.760 ;
      RECT 80.520 0.840 80.800 249.760 ;
      RECT 82.760 0.840 83.040 249.760 ;
      RECT 85.000 0.840 85.280 249.760 ;
      RECT 87.240 0.840 87.520 249.760 ;
      RECT 89.480 0.840 89.760 249.760 ;
      RECT 91.720 0.840 92.000 249.760 ;
      RECT 93.960 0.840 94.240 249.760 ;
      RECT 96.200 0.840 96.480 249.760 ;
    END
  END VDD
  OBS
    LAYER metal1 ;
    RECT 0 0 96.710 250.600 ;
    LAYER metal2 ;
    RECT 0 0 96.710 250.600 ;
    LAYER metal3 ;
    RECT 0 0 96.710 250.600 ;
    LAYER metal4 ;
    RECT 0 0 96.710 250.600 ;
    LAYER OVERLAP ;
    RECT 0 0 96.710 250.600 ;
  END
END fakeram_32x128_2r1w

END LIBRARY
